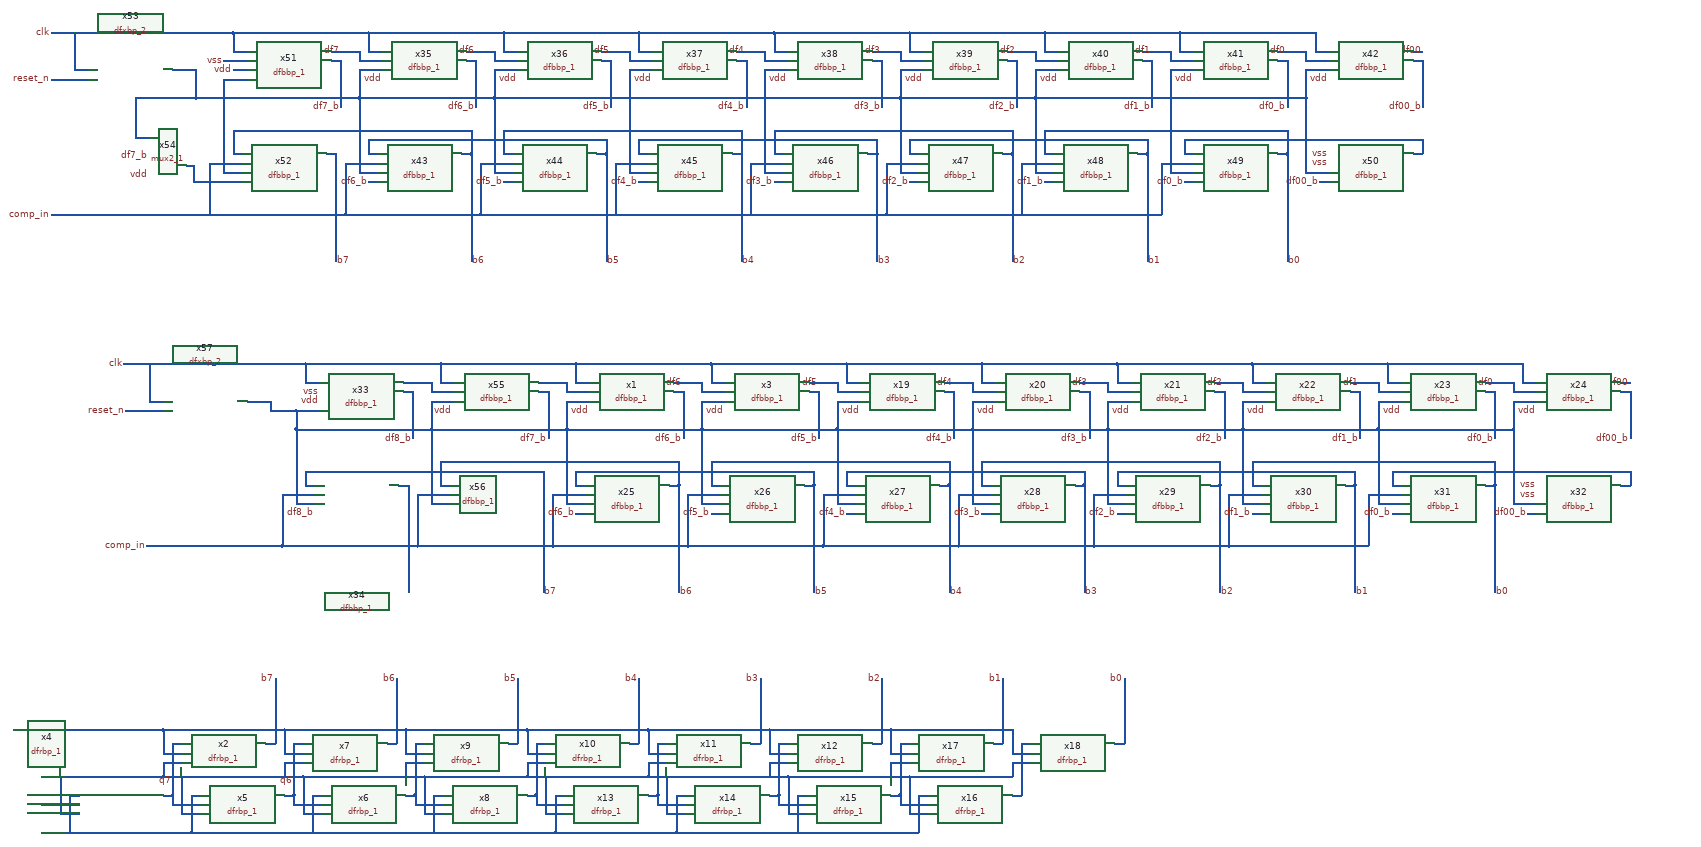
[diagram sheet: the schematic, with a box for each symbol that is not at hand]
v {xschem version=3.4.6RC file_version=1.2
}
G {}
K {}
V {}
S {}
E {}
N 440 -240 460 -240 {lab=q7}
N 420 -220 460 -220 {lab=#net1}
N 420 -270 420 -220 {lab=#net1}
N 160 -270 420 -270 {lab=#net1}
N 160 -110 240 -110 {lab=#net2}
N 220 -130 240 -130 {lab=#net3}
N 220 -130 220 -50 {lab=#net3}
N 160 -50 220 -50 {lab=#net3}
N 640 -240 660 -240 {lab=b7}
N 700 -240 720 -240 {lab=q6}
N 420 -200 460 -200 {lab=#net4}
N 420 -200 420 -170 {lab=#net4}
N 200 -90 240 -90 {lab=#net4}
N 200 -170 200 -90 {lab=#net4}
N 480 -130 500 -130 {lab=#net3}
N 480 -130 480 -50 {lab=#net3}
N 460 -90 500 -90 {lab=#net4}
N 460 -170 460 -90 {lab=#net4}
N 440 -110 500 -110 {lab=q7}
N 440 -130 440 -110 {lab=q7}
N 420 -130 440 -130 {lab=q7}
N 220 -50 480 -50 {lab=#net3}
N 440 -240 440 -130 {lab=q7}
N 680 -130 700 -130 {lab=q6}
N 700 -240 700 -130 {lab=q6}
N 680 -200 720 -200 {lab=#net4}
N 680 -200 680 -170 {lab=#net4}
N 420 -170 680 -170 {lab=#net4}
N 160 -170 420 -170 {lab=#net4}
N 680 -220 720 -220 {lab=#net1}
N 680 -270 680 -220 {lab=#net1}
N 420 -270 680 -270 {lab=#net1}
N 740 -130 760 -130 {lab=#net3}
N 740 -130 740 -50 {lab=#net3}
N 720 -90 760 -90 {lab=#net4}
N 720 -170 720 -90 {lab=#net4}
N 1000 -130 1020 -130 {lab=#net3}
N 1000 -130 1000 -50 {lab=#net3}
N 980 -90 1020 -90 {lab=#net4}
N 980 -170 980 -90 {lab=#net4}
N 960 -110 1020 -110 {lab=#net5}
N 960 -130 960 -110 {lab=#net5}
N 940 -130 960 -130 {lab=#net5}
N 740 -50 1000 -50 {lab=#net3}
N 960 -240 960 -130 {lab=#net5}
N 700 -110 760 -110 {lab=q6}
N 700 -130 700 -110 {lab=q6}
N 480 -50 740 -50 {lab=#net3}
N 680 -170 720 -170 {lab=#net4}
N 960 -240 980 -240 {lab=#net5}
N 720 -170 980 -170 {lab=#net4}
N 940 -220 980 -220 {lab=#net1}
N 940 -270 940 -220 {lab=#net1}
N 680 -270 940 -270 {lab=#net1}
N 940 -200 980 -200 {lab=#net4}
N 940 -200 940 -170 {lab=#net4}
N 1160 -240 1180 -240 {lab=b5}
N 1180 -380 1180 -240 {lab=b5}
N 900 -240 920 -240 {lab=b6}
N 920 -380 920 -240 {lab=b6}
N 660 -380 660 -240 {lab=b7}
N 1200 -130 1220 -130 {lab=#net6}
N 1220 -240 1220 -130 {lab=#net6}
N 1220 -240 1240 -240 {lab=#net6}
N 1200 -220 1240 -220 {lab=#net1}
N 1200 -270 1200 -220 {lab=#net1}
N 940 -270 1200 -270 {lab=#net1}
N 1200 -200 1240 -200 {lab=#net4}
N 1200 -200 1200 -170 {lab=#net4}
N 980 -170 1200 -170 {lab=#net4}
N 1420 -240 1440 -240 {lab=b4}
N 1440 -380 1440 -240 {lab=b4}
N 1480 -240 1500 -240 {lab=#net7}
N 1460 -220 1500 -220 {lab=#net1}
N 1460 -270 1460 -220 {lab=#net1}
N 1260 -130 1280 -130 {lab=#net3}
N 1260 -130 1260 -50 {lab=#net3}
N 1680 -240 1700 -240 {lab=b3}
N 1740 -240 1760 -240 {lab=#net8}
N 1460 -200 1500 -200 {lab=#net4}
N 1460 -200 1460 -170 {lab=#net4}
N 1520 -130 1540 -130 {lab=#net3}
N 1520 -130 1520 -50 {lab=#net3}
N 1500 -90 1540 -90 {lab=#net4}
N 1500 -170 1500 -90 {lab=#net4}
N 1480 -110 1540 -110 {lab=#net7}
N 1480 -130 1480 -110 {lab=#net7}
N 1460 -130 1480 -130 {lab=#net7}
N 1260 -50 1520 -50 {lab=#net3}
N 1480 -240 1480 -130 {lab=#net7}
N 1720 -130 1740 -130 {lab=#net8}
N 1740 -240 1740 -130 {lab=#net8}
N 1720 -200 1760 -200 {lab=#net4}
N 1720 -200 1720 -170 {lab=#net4}
N 1460 -170 1720 -170 {lab=#net4}
N 1720 -220 1760 -220 {lab=#net1}
N 1720 -270 1720 -220 {lab=#net1}
N 1460 -270 1720 -270 {lab=#net1}
N 1780 -130 1800 -130 {lab=#net3}
N 1780 -130 1780 -50 {lab=#net3}
N 1760 -90 1800 -90 {lab=#net4}
N 1760 -170 1760 -90 {lab=#net4}
N 2040 -130 2060 -130 {lab=#net3}
N 2040 -130 2040 -50 {lab=#net3}
N 2020 -90 2060 -90 {lab=#net4}
N 2020 -170 2020 -90 {lab=#net4}
N 2000 -110 2060 -110 {lab=#net9}
N 2000 -130 2000 -110 {lab=#net9}
N 1980 -130 2000 -130 {lab=#net9}
N 1780 -50 2040 -50 {lab=#net3}
N 2000 -240 2000 -130 {lab=#net9}
N 1740 -110 1800 -110 {lab=#net8}
N 1740 -130 1740 -110 {lab=#net8}
N 1520 -50 1780 -50 {lab=#net3}
N 1720 -170 1760 -170 {lab=#net4}
N 2000 -240 2020 -240 {lab=#net9}
N 1760 -170 2020 -170 {lab=#net4}
N 1980 -220 2020 -220 {lab=#net1}
N 1980 -270 1980 -220 {lab=#net1}
N 1720 -270 1980 -270 {lab=#net1}
N 1980 -200 2020 -200 {lab=#net4}
N 1980 -200 1980 -170 {lab=#net4}
N 2200 -240 2220 -240 {lab=b1}
N 2220 -380 2220 -240 {lab=b1}
N 1940 -240 1960 -240 {lab=b2}
N 1960 -380 1960 -240 {lab=b2}
N 1700 -380 1700 -240 {lab=b3}
N 2240 -130 2260 -130 {lab=#net10}
N 2260 -240 2260 -130 {lab=#net10}
N 2260 -240 2280 -240 {lab=#net10}
N 2240 -220 2280 -220 {lab=#net1}
N 2240 -270 2240 -220 {lab=#net1}
N 1980 -270 2240 -270 {lab=#net1}
N 2240 -200 2280 -200 {lab=#net4}
N 2240 -200 2240 -170 {lab=#net4}
N 2020 -170 2240 -170 {lab=#net4}
N 2460 -240 2480 -240 {lab=b0}
N 2480 -380 2480 -240 {lab=b0}
N 1200 -270 1460 -270 {lab=#net1}
N 1200 -170 1460 -170 {lab=#net4}
N 1000 -50 1260 -50 {lab=#net3}
N 1220 -130 1220 -110 {lab=#net6}
N 1220 -110 1280 -110 {lab=#net6}
N 1240 -90 1280 -90 {lab=#net4}
N 1240 -170 1240 -90 {lab=#net4}
N 100 -270 160 -270 {lab=#net1}
N 1305 -1015 1335 -1015 {lab=clk}
N 1285 -995 1335 -995 {lab=#net12}
N 2735 -975 2785 -975 {lab=#net13}
N 2735 -975 2735 -915 {lab=#net13}
N 2755 -1015 2785 -1015 {lab=clk}
N 2755 -1055 2755 -1015 {lab=clk}
N 2735 -995 2785 -995 {lab=df2}
N 2735 -1015 2735 -995 {lab=df2}
N 1515 -1015 1575 -1015 {lab=df6}
N 3025 -975 3075 -975 {lab=#net13}
N 3025 -975 3025 -915 {lab=#net13}
N 3045 -1015 3075 -1015 {lab=clk}
N 3045 -1055 3045 -1015 {lab=clk}
N 3025 -995 3075 -995 {lab=df1}
N 3025 -1015 3025 -995 {lab=df1}
N 2965 -1015 3025 -1015 {lab=df1}
N 3315 -975 3365 -975 {lab=#net13}
N 3315 -975 3315 -915 {lab=#net13}
N 3335 -1015 3365 -1015 {lab=clk}
N 3335 -1055 3335 -1015 {lab=clk}
N 3315 -995 3365 -995 {lab=df0}
N 3315 -1015 3315 -995 {lab=df0}
N 3255 -1015 3315 -1015 {lab=df0}
N 1305 -1055 1595 -1055 {lab=clk}
N 2755 -1055 3045 -1055 {lab=clk}
N 3045 -1055 3335 -1055 {lab=clk}
N 1285 -915 1575 -915 {lab=#net13}
N 2735 -915 3025 -915 {lab=#net13}
N 3025 -915 3315 -915 {lab=#net13}
N 1515 -995 1535 -995 {lab=df6_b}
N 1535 -995 1535 -895 {lab=df6_b}
N 2965 -995 2985 -995 {lab=df1_b}
N 2985 -995 2985 -895 {lab=df1_b}
N 3255 -995 3275 -995 {lab=df0_b}
N 3275 -995 3275 -895 {lab=df0_b}
N 3545 -995 3565 -995 {lab=df00_b}
N 3565 -995 3565 -895 {lab=df00_b}
N 3545 -1015 3565 -1015 {lab=df00}
N 1575 -975 1625 -975 {lab=#net13}
N 1575 -975 1575 -915 {lab=#net13}
N 1595 -1015 1625 -1015 {lab=clk}
N 1595 -1055 1595 -1015 {lab=clk}
N 1575 -995 1625 -995 {lab=df6}
N 1575 -1015 1575 -995 {lab=df6}
N 1805 -1015 1865 -1015 {lab=df5}
N 1595 -1055 1885 -1055 {lab=clk}
N 1575 -915 1865 -915 {lab=#net13}
N 1805 -995 1825 -995 {lab=df5_b}
N 1825 -995 1825 -895 {lab=df5_b}
N 1865 -975 1915 -975 {lab=#net13}
N 1865 -975 1865 -915 {lab=#net13}
N 1885 -1015 1915 -1015 {lab=clk}
N 1885 -1055 1885 -1015 {lab=clk}
N 1865 -995 1915 -995 {lab=df5}
N 1865 -1015 1865 -995 {lab=df5}
N 2095 -1015 2155 -1015 {lab=df4}
N 1885 -1055 2175 -1055 {lab=clk}
N 1865 -915 2155 -915 {lab=#net13}
N 2095 -995 2115 -995 {lab=df4_b}
N 2115 -995 2115 -895 {lab=df4_b}
N 2155 -975 2205 -975 {lab=#net13}
N 2155 -975 2155 -915 {lab=#net13}
N 2175 -1015 2205 -1015 {lab=clk}
N 2175 -1055 2175 -1015 {lab=clk}
N 2155 -995 2205 -995 {lab=df4}
N 2155 -1015 2155 -995 {lab=df4}
N 2385 -1015 2445 -1015 {lab=df3}
N 2175 -1055 2465 -1055 {lab=clk}
N 2155 -915 2445 -915 {lab=#net13}
N 2385 -995 2405 -995 {lab=df3_b}
N 2405 -995 2405 -895 {lab=df3_b}
N 2445 -975 2495 -975 {lab=#net13}
N 2445 -975 2445 -915 {lab=#net13}
N 2465 -1015 2495 -1015 {lab=clk}
N 2465 -1055 2465 -1015 {lab=clk}
N 2445 -995 2495 -995 {lab=df3}
N 2445 -1015 2445 -995 {lab=df3}
N 2675 -1015 2735 -1015 {lab=df2}
N 2465 -1055 2755 -1055 {lab=clk}
N 2445 -915 2735 -915 {lab=#net13}
N 2675 -995 2695 -995 {lab=df2_b}
N 2695 -995 2695 -895 {lab=df2_b}
N 3345 -735 3365 -735 {lab=df00_b}
N 3545 -795 3565 -795 {lab=#net14}
N 3565 -825 3565 -795 {lab=#net14}
N 3055 -795 3075 -795 {lab=#net14}
N 3055 -825 3055 -795 {lab=#net14}
N 3055 -735 3075 -735 {lab=df0_b}
N 3255 -795 3275 -795 {lab=b0}
N 3275 -845 3275 -795 {lab=b0}
N 2755 -845 2755 -795 {lab=b0}
N 2755 -795 2775 -795 {lab=b0}
N 2755 -845 3275 -845 {lab=b0}
N 2955 -795 2975 -795 {lab=b1}
N 2975 -825 2975 -795 {lab=b1}
N 2465 -795 2485 -795 {lab=b1}
N 2465 -825 2465 -795 {lab=b1}
N 2465 -825 2975 -825 {lab=b1}
N 2665 -795 2685 -795 {lab=b2}
N 2685 -845 2685 -795 {lab=b2}
N 2175 -795 2195 -795 {lab=b2}
N 2175 -845 2175 -795 {lab=b2}
N 2175 -845 2685 -845 {lab=b2}
N 2175 -735 2195 -735 {lab=df3_b}
N 2465 -735 2485 -735 {lab=df2_b}
N 2755 -735 2775 -735 {lab=df1_b}
N 2125 -775 2125 -665 {lab=#net15}
N 2415 -775 2415 -665 {lab=#net15}
N 2375 -795 2395 -795 {lab=b3}
N 2705 -775 2705 -665 {lab=#net15}
N 1885 -795 1905 -795 {lab=b3}
N 1885 -825 1885 -795 {lab=b3}
N 1885 -825 2395 -825 {lab=b3}
N 2085 -795 2105 -795 {lab=b4}
N 2105 -845 2105 -795 {lab=b4}
N 1595 -795 1615 -795 {lab=b4}
N 1595 -845 1595 -795 {lab=b4}
N 1595 -845 2105 -845 {lab=b4}
N 1595 -735 1615 -735 {lab=df5_b}
N 1885 -735 1905 -735 {lab=df4_b}
N 1835 -775 1835 -665 {lab=#net15}
N 1795 -795 1815 -795 {lab=b5}
N 2395 -825 2395 -795 {lab=b3}
N 1545 -775 1545 -665 {lab=#net15}
N 725 -795 745 -795 {lab=b7}
N 1505 -795 1525 -795 {lab=b6}
N 1525 -845 1525 -795 {lab=b6}
N 1815 -825 1815 -795 {lab=b5}
N 1545 -775 1615 -775 {lab=#net15}
N 1525 -795 1525 -565 {lab=b6}
N 1815 -795 1815 -565 {lab=b5}
N 1835 -775 1905 -775 {lab=#net15}
N 2125 -775 2195 -775 {lab=#net15}
N 2105 -795 2105 -565 {lab=b4}
N 2415 -775 2485 -775 {lab=#net15}
N 2395 -795 2395 -565 {lab=b3}
N 2685 -795 2685 -565 {lab=b2}
N 2705 -775 2775 -775 {lab=#net15}
N 2975 -795 2975 -565 {lab=b1}
N 3005 -775 3075 -775 {lab=#net15}
N 3275 -795 3275 -565 {lab=b0}
N 3055 -825 3565 -825 {lab=#net14}
N 1225 -995 1245 -995 {lab=df7_b}
N 1245 -995 1245 -895 {lab=df7_b}
N 1305 -825 1305 -795 {lab=b5}
N 1305 -795 1325 -795 {lab=b5}
N 925 -795 945 -795 {lab=#net16}
N 1545 -665 1835 -665 {lab=#net15}
N 1835 -665 2125 -665 {lab=#net15}
N 2125 -665 2415 -665 {lab=#net15}
N 2415 -665 2705 -665 {lab=#net15}
N 2705 -665 3005 -665 {lab=#net15}
N 3005 -775 3005 -665 {lab=#net15}
N 1305 -1055 1305 -1015 {lab=clk}
N 945 -795 945 -565 {lab=#net16}
N 1255 -665 1545 -665 {lab=#net15}
N 1305 -825 1815 -825 {lab=b5}
N 1015 -845 1525 -845 {lab=b6}
N 1305 -735 1325 -735 {lab=df6_b}
N 1285 -755 1325 -755 {lab=#net13}
N 1575 -915 1575 -755 {lab=#net13}
N 1575 -755 1615 -755 {lab=#net13}
N 1865 -915 1865 -755 {lab=#net13}
N 1865 -755 1905 -755 {lab=#net13}
N 2155 -915 2155 -755 {lab=#net13}
N 2155 -755 2195 -755 {lab=#net13}
N 2445 -915 2445 -755 {lab=#net13}
N 2445 -755 2485 -755 {lab=#net13}
N 2735 -915 2735 -755 {lab=#net13}
N 2735 -755 2775 -755 {lab=#net13}
N 3025 -915 3025 -755 {lab=#net13}
N 3025 -755 3075 -755 {lab=#net13}
N 3315 -915 3315 -755 {lab=#net13}
N 3315 -755 3365 -755 {lab=#net13}
N 280 -1765 570 -1765 {lab=clk}
N 840 -1685 890 -1685 {lab=#net17}
N 860 -1725 890 -1725 {lab=clk}
N 570 -1765 570 -1725 {lab=clk}
N 840 -1705 890 -1705 {lab=df7}
N 2290 -1685 2340 -1685 {lab=#net17}
N 2290 -1685 2290 -1625 {lab=#net17}
N 2310 -1725 2340 -1725 {lab=clk}
N 2310 -1765 2310 -1725 {lab=clk}
N 2290 -1705 2340 -1705 {lab=df2}
N 2290 -1725 2290 -1705 {lab=df2}
N 1070 -1725 1130 -1725 {lab=df6}
N 2580 -1685 2630 -1685 {lab=#net17}
N 2580 -1685 2580 -1625 {lab=#net17}
N 2600 -1725 2630 -1725 {lab=clk}
N 2600 -1765 2600 -1725 {lab=clk}
N 2580 -1705 2630 -1705 {lab=df1}
N 2580 -1725 2580 -1705 {lab=df1}
N 2520 -1725 2580 -1725 {lab=df1}
N 2870 -1685 2920 -1685 {lab=#net17}
N 2870 -1685 2870 -1625 {lab=#net17}
N 2890 -1725 2920 -1725 {lab=clk}
N 2890 -1765 2890 -1725 {lab=clk}
N 2870 -1705 2920 -1705 {lab=df0}
N 2870 -1725 2870 -1705 {lab=df0}
N 2810 -1725 2870 -1725 {lab=df0}
N 860 -1765 1150 -1765 {lab=clk}
N 2310 -1765 2600 -1765 {lab=clk}
N 2600 -1765 2890 -1765 {lab=clk}
N 840 -1625 1130 -1625 {lab=#net17}
N 2290 -1625 2580 -1625 {lab=#net17}
N 2580 -1625 2870 -1625 {lab=#net17}
N 1070 -1705 1090 -1705 {lab=df6_b}
N 1090 -1705 1090 -1605 {lab=df6_b}
N 2520 -1705 2540 -1705 {lab=df1_b}
N 2540 -1705 2540 -1605 {lab=df1_b}
N 2810 -1705 2830 -1705 {lab=df0_b}
N 2830 -1705 2830 -1605 {lab=df0_b}
N 3100 -1705 3120 -1705 {lab=df00_b}
N 3120 -1705 3120 -1605 {lab=df00_b}
N 3100 -1725 3120 -1725 {lab=df00}
N 1130 -1685 1180 -1685 {lab=#net17}
N 1130 -1685 1130 -1625 {lab=#net17}
N 1150 -1725 1180 -1725 {lab=clk}
N 1150 -1765 1150 -1725 {lab=clk}
N 1130 -1705 1180 -1705 {lab=df6}
N 1130 -1725 1130 -1705 {lab=df6}
N 1360 -1725 1420 -1725 {lab=df5}
N 1150 -1765 1440 -1765 {lab=clk}
N 1130 -1625 1420 -1625 {lab=#net17}
N 1360 -1705 1380 -1705 {lab=df5_b}
N 1380 -1705 1380 -1605 {lab=df5_b}
N 1420 -1685 1470 -1685 {lab=#net17}
N 1420 -1685 1420 -1625 {lab=#net17}
N 1440 -1725 1470 -1725 {lab=clk}
N 1440 -1765 1440 -1725 {lab=clk}
N 1420 -1705 1470 -1705 {lab=df5}
N 1420 -1725 1420 -1705 {lab=df5}
N 1650 -1725 1710 -1725 {lab=df4}
N 1440 -1765 1730 -1765 {lab=clk}
N 1420 -1625 1710 -1625 {lab=#net17}
N 1650 -1705 1670 -1705 {lab=df4_b}
N 1670 -1705 1670 -1605 {lab=df4_b}
N 1710 -1685 1760 -1685 {lab=#net17}
N 1710 -1685 1710 -1625 {lab=#net17}
N 1730 -1725 1760 -1725 {lab=clk}
N 1730 -1765 1730 -1725 {lab=clk}
N 1710 -1705 1760 -1705 {lab=df4}
N 1710 -1725 1710 -1705 {lab=df4}
N 1940 -1725 2000 -1725 {lab=df3}
N 1730 -1765 2020 -1765 {lab=clk}
N 1710 -1625 2000 -1625 {lab=#net17}
N 1940 -1705 1960 -1705 {lab=df3_b}
N 1960 -1705 1960 -1605 {lab=df3_b}
N 2000 -1685 2050 -1685 {lab=#net17}
N 2000 -1685 2000 -1625 {lab=#net17}
N 2020 -1725 2050 -1725 {lab=clk}
N 2020 -1765 2020 -1725 {lab=clk}
N 2000 -1705 2050 -1705 {lab=df3}
N 2000 -1725 2000 -1705 {lab=df3}
N 2230 -1725 2290 -1725 {lab=df2}
N 2020 -1765 2310 -1765 {lab=clk}
N 2000 -1625 2290 -1625 {lab=#net17}
N 2230 -1705 2250 -1705 {lab=df2_b}
N 2250 -1705 2250 -1605 {lab=df2_b}
N 2900 -1445 2920 -1445 {lab=df00_b}
N 3100 -1505 3120 -1505 {lab=#net18}
N 3120 -1535 3120 -1505 {lab=#net18}
N 2610 -1505 2630 -1505 {lab=#net18}
N 2610 -1535 2610 -1505 {lab=#net18}
N 2610 -1445 2630 -1445 {lab=df0_b}
N 2810 -1505 2830 -1505 {lab=b0}
N 2830 -1555 2830 -1505 {lab=b0}
N 2310 -1555 2310 -1505 {lab=b0}
N 2310 -1505 2330 -1505 {lab=b0}
N 2310 -1555 2830 -1555 {lab=b0}
N 2510 -1505 2530 -1505 {lab=b1}
N 2530 -1535 2530 -1505 {lab=b1}
N 2020 -1505 2040 -1505 {lab=b1}
N 2020 -1535 2020 -1505 {lab=b1}
N 2020 -1535 2530 -1535 {lab=b1}
N 2220 -1505 2240 -1505 {lab=b2}
N 2240 -1555 2240 -1505 {lab=b2}
N 1730 -1505 1750 -1505 {lab=b2}
N 1730 -1555 1730 -1505 {lab=b2}
N 1730 -1555 2240 -1555 {lab=b2}
N 1730 -1445 1750 -1445 {lab=df3_b}
N 2020 -1445 2040 -1445 {lab=df2_b}
N 2310 -1445 2330 -1445 {lab=df1_b}
N 1680 -1485 1680 -1375 {lab=comp_in}
N 1970 -1485 1970 -1375 {lab=comp_in}
N 1930 -1505 1950 -1505 {lab=b3}
N 2260 -1485 2260 -1375 {lab=comp_in}
N 1440 -1505 1460 -1505 {lab=b3}
N 1440 -1535 1440 -1505 {lab=b3}
N 1440 -1535 1950 -1535 {lab=b3}
N 1640 -1505 1660 -1505 {lab=b4}
N 1660 -1555 1660 -1505 {lab=b4}
N 1150 -1505 1170 -1505 {lab=b4}
N 1150 -1555 1150 -1505 {lab=b4}
N 1150 -1555 1660 -1555 {lab=b4}
N 1150 -1445 1170 -1445 {lab=df5_b}
N 1440 -1445 1460 -1445 {lab=df4_b}
N 1390 -1485 1390 -1375 {lab=comp_in}
N 1350 -1505 1370 -1505 {lab=b5}
N 1950 -1535 1950 -1505 {lab=b3}
N 1100 -1485 1100 -1375 {lab=comp_in}
N 570 -1505 590 -1505 {lab=b6}
N 1060 -1505 1080 -1505 {lab=b6}
N 1080 -1555 1080 -1505 {lab=b6}
N 570 -1445 590 -1445 {lab=#net19}
N 1370 -1535 1370 -1505 {lab=b5}
N 520 -1485 520 -1375 {lab=comp_in}
N 520 -1485 590 -1485 {lab=comp_in}
N 1100 -1485 1170 -1485 {lab=comp_in}
N 1080 -1505 1080 -1275 {lab=b6}
N 1370 -1505 1370 -1275 {lab=b5}
N 1390 -1485 1460 -1485 {lab=comp_in}
N 1680 -1485 1750 -1485 {lab=comp_in}
N 1660 -1505 1660 -1275 {lab=b4}
N 1970 -1485 2040 -1485 {lab=comp_in}
N 1950 -1505 1950 -1275 {lab=b3}
N 2240 -1505 2240 -1275 {lab=b2}
N 2260 -1485 2330 -1485 {lab=comp_in}
N 2530 -1505 2530 -1275 {lab=b1}
N 2560 -1485 2630 -1485 {lab=comp_in}
N 2830 -1505 2830 -1275 {lab=b0}
N 2610 -1535 3120 -1535 {lab=#net18}
N 570 -1725 600 -1725 {lab=clk}
N 550 -1705 600 -1705 {lab=vss}
N 780 -1725 840 -1725 {lab=df7}
N 550 -1625 840 -1625 {lab=#net17}
N 780 -1705 800 -1705 {lab=df7_b}
N 800 -1705 800 -1605 {lab=df7_b}
N 840 -1685 840 -1625 {lab=#net17}
N 840 -1725 840 -1705 {lab=df7}
N 810 -1485 880 -1485 {lab=comp_in}
N 860 -1535 860 -1505 {lab=b5}
N 860 -1505 880 -1505 {lab=b5}
N 770 -1505 790 -1505 {lab=b7}
N 570 -1555 570 -1505 {lab=b6}
N 180 -1375 230 -1375 {lab=comp_in}
N 230 -1375 520 -1375 {lab=comp_in}
N 1100 -1375 1390 -1375 {lab=comp_in}
N 1390 -1375 1680 -1375 {lab=comp_in}
N 1680 -1375 1970 -1375 {lab=comp_in}
N 1970 -1375 2260 -1375 {lab=comp_in}
N 2260 -1375 2560 -1375 {lab=comp_in}
N 2560 -1485 2560 -1375 {lab=comp_in}
N 570 -1765 860 -1765 {lab=clk}
N 860 -1765 860 -1725 {lab=clk}
N 790 -1505 790 -1275 {lab=b7}
N 810 -1485 810 -1375 {lab=comp_in}
N 520 -1375 810 -1375 {lab=comp_in}
N 810 -1375 1100 -1375 {lab=comp_in}
N 860 -1535 1370 -1535 {lab=b5}
N 570 -1555 1080 -1555 {lab=b6}
N 860 -1445 880 -1445 {lab=df6_b}
N 550 -1625 550 -1465 {lab=#net17}
N 550 -1465 590 -1465 {lab=#net17}
N 840 -1625 840 -1465 {lab=#net17}
N 840 -1465 880 -1465 {lab=#net17}
N 1130 -1625 1130 -1465 {lab=#net17}
N 1130 -1465 1170 -1465 {lab=#net17}
N 1420 -1625 1420 -1465 {lab=#net17}
N 1420 -1465 1460 -1465 {lab=#net17}
N 1710 -1625 1710 -1465 {lab=#net17}
N 1710 -1465 1750 -1465 {lab=#net17}
N 2000 -1625 2000 -1465 {lab=#net17}
N 2000 -1465 2040 -1465 {lab=#net17}
N 2290 -1625 2290 -1465 {lab=#net17}
N 2290 -1465 2330 -1465 {lab=#net17}
N 2580 -1625 2580 -1465 {lab=#net17}
N 2580 -1465 2630 -1465 {lab=#net17}
N 2870 -1625 2870 -1465 {lab=#net17}
N 2870 -1465 2920 -1465 {lab=#net17}
N 180 -1665 260 -1665 {lab=reset_n}
N 180 -1765 280 -1765 {lab=clk}
N 230 -1685 260 -1685 {lab=clk}
N 230 -1765 230 -1685 {lab=clk}
N 570 -1685 600 -1685 {lab=vdd}
N 490 -1685 490 -1625 {lab=#net17}
N 550 -1665 550 -1625 {lab=#net17}
N 550 -1665 600 -1665 {lab=#net17}
N 490 -1625 550 -1625 {lab=#net17}
N 440 -1685 490 -1685 {lab=#net17}
N 470 -1480 485 -1480 {lab=#net19}
N 485 -1480 485 -1445 {lab=#net19}
N 485 -1445 570 -1445 {lab=#net19}
N 360 -1625 490 -1625 {lab=#net17}
N 360 -1625 360 -1540 {lab=#net17}
N 360 -1540 390 -1540 {lab=#net17}
N 1225 -1015 1285 -1015 {lab=#net12}
N 1285 -1015 1285 -995 {lab=#net12}
N 1015 -795 1035 -795 {lab=b6}
N 1235 -795 1235 -565 {lab=b7}
N 1285 -915 1285 -755 {lab=#net13}
N 1015 -845 1015 -795 {lab=b6}
N 1235 -825 1235 -795 {lab=b7}
N 725 -825 725 -795 {lab=b7}
N 725 -825 1235 -825 {lab=b7}
N 995 -755 1035 -755 {lab=#net13}
N 995 -915 995 -755 {lab=#net13}
N 995 -915 1285 -915 {lab=#net13}
N 705 -755 745 -755 {lab=#net20}
N 705 -915 705 -755 {lab=#net20}
N 995 -995 1045 -995 {lab=#net21}
N 935 -1015 995 -1015 {lab=#net21}
N 995 -1015 995 -995 {lab=#net21}
N 725 -1015 755 -1015 {lab=clk}
N 725 -1055 725 -1015 {lab=clk}
N 1015 -1055 1305 -1055 {lab=clk}
N 725 -1055 1015 -1055 {lab=clk}
N 1015 -1015 1045 -1015 {lab=clk}
N 1015 -1055 1015 -1015 {lab=clk}
N 705 -955 705 -915 {lab=#net20}
N 705 -955 755 -955 {lab=#net20}
N 935 -995 955 -995 {lab=df8_b}
N 955 -995 955 -895 {lab=df8_b}
N 385 -665 675 -665 {lab=#net15}
N 675 -665 965 -665 {lab=#net15}
N 965 -665 1255 -665 {lab=#net15}
N 435 -1055 725 -1055 {lab=clk}
N 335 -1055 435 -1055 {lab=clk}
N 340 -955 420 -955 {lab=reset_n}
N 390 -975 420 -975 {lab=clk}
N 390 -1055 390 -975 {lab=clk}
N 600 -975 650 -975 {lab=#net20}
N 650 -955 705 -955 {lab=#net20}
N 650 -975 650 -955 {lab=#net20}
N 1255 -775 1255 -665 {lab=#net15}
N 1255 -775 1325 -775 {lab=#net15}
N 965 -775 965 -665 {lab=#net15}
N 965 -775 1035 -775 {lab=#net15}
N 675 -775 675 -665 {lab=#net15}
N 675 -775 745 -775 {lab=#net15}
N 705 -915 995 -915 {lab=#net13}
N 1285 -975 1335 -975 {lab=#net13}
N 1285 -975 1285 -915 {lab=#net13}
N 995 -975 1045 -975 {lab=#net13}
N 995 -975 995 -915 {lab=#net13}
C {sky130_stdcells/dfrbp_1.sym} 550 -220 0 0 {name=x2 VGND=vss VNB=vss VPB=vdd VPWR=vdd prefix=sky130_fd_sc_hd__ }
C {sky130_stdcells/dfrbp_1.sym} 810 -220 0 0 {name=x7 VGND=vss VNB=vss VPB=vdd VPWR=vdd prefix=sky130_fd_sc_hd__ }
C {sky130_stdcells/dfrbp_1.sym} 330 -110 0 0 {name=x4 VGND=vss VNB=vss VPB=vdd VPWR=vdd prefix=sky130_fd_sc_hd__ }
C {sky130_stdcells/dfrbp_1.sym} 590 -110 0 0 {name=x5 VGND=vss VNB=vss VPB=vdd VPWR=vdd prefix=sky130_fd_sc_hd__ }
C {sky130_stdcells/dfrbp_1.sym} 850 -110 0 0 {name=x6 VGND=vss VNB=vss VPB=vdd VPWR=vdd prefix=sky130_fd_sc_hd__ }
C {sky130_stdcells/dfrbp_1.sym} 1110 -110 0 0 {name=x8 VGND=vss VNB=vss VPB=vdd VPWR=vdd prefix=sky130_fd_sc_hd__ }
C {sky130_stdcells/dfrbp_1.sym} 1070 -220 0 0 {name=x9 VGND=vss VNB=vss VPB=vdd VPWR=vdd prefix=sky130_fd_sc_hd__ }
C {sky130_stdcells/dfrbp_1.sym} 1330 -220 0 0 {name=x10 VGND=vss VNB=vss VPB=vdd VPWR=vdd prefix=sky130_fd_sc_hd__ }
C {sky130_stdcells/dfrbp_1.sym} 1590 -220 0 0 {name=x11 VGND=vss VNB=vss VPB=vdd VPWR=vdd prefix=sky130_fd_sc_hd__ }
C {sky130_stdcells/dfrbp_1.sym} 1850 -220 0 0 {name=x12 VGND=vss VNB=vss VPB=vdd VPWR=vdd prefix=sky130_fd_sc_hd__ }
C {sky130_stdcells/dfrbp_1.sym} 1370 -110 0 0 {name=x13 VGND=vss VNB=vss VPB=vdd VPWR=vdd prefix=sky130_fd_sc_hd__ }
C {sky130_stdcells/dfrbp_1.sym} 1630 -110 0 0 {name=x14 VGND=vss VNB=vss VPB=vdd VPWR=vdd prefix=sky130_fd_sc_hd__ }
C {sky130_stdcells/dfrbp_1.sym} 1890 -110 0 0 {name=x15 VGND=vss VNB=vss VPB=vdd VPWR=vdd prefix=sky130_fd_sc_hd__ }
C {sky130_stdcells/dfrbp_1.sym} 2150 -110 0 0 {name=x16 VGND=vss VNB=vss VPB=vdd VPWR=vdd prefix=sky130_fd_sc_hd__ }
C {sky130_stdcells/dfrbp_1.sym} 2110 -220 0 0 {name=x17 VGND=vss VNB=vss VPB=vdd VPWR=vdd prefix=sky130_fd_sc_hd__ }
C {sky130_stdcells/dfrbp_1.sym} 2370 -220 0 0 {name=x18 VGND=vss VNB=vss VPB=vdd VPWR=vdd prefix=sky130_fd_sc_hd__ }
C {lab_pin.sym} 2480 -380 0 0 {name=p10 sig_type=std_logic lab=b0
}
C {lab_pin.sym} 2220 -380 0 0 {name=p11 sig_type=std_logic lab=b1
}
C {lab_pin.sym} 1960 -380 0 0 {name=p14 sig_type=std_logic lab=b2
}
C {lab_pin.sym} 1700 -380 0 0 {name=p16 sig_type=std_logic lab=b3
}
C {lab_pin.sym} 1440 -380 0 0 {name=p17 sig_type=std_logic lab=b4
}
C {lab_pin.sym} 1180 -380 0 0 {name=p18 sig_type=std_logic lab=b5
}
C {lab_pin.sym} 920 -380 0 0 {name=p20 sig_type=std_logic lab=b6
}
C {lab_pin.sym} 660 -380 0 0 {name=p21 sig_type=std_logic lab=b7
}
C {lab_pin.sym} 440 -160 0 0 {name=p54 sig_type=std_logic lab=q7
}
C {lab_pin.sym} 700 -160 0 0 {name=p53 sig_type=std_logic lab=q6
}
C {lab_pin.sym} 1335 -955 0 0 {name=p24 sig_type=std_logic lab=vdd
}
C {lab_pin.sym} 2785 -955 0 0 {name=p26 sig_type=std_logic lab=vdd
}
C {lab_pin.sym} 3075 -955 0 0 {name=p1 sig_type=std_logic lab=vdd
}
C {lab_pin.sym} 3365 -955 0 0 {name=p55 sig_type=std_logic lab=vdd
}
C {lab_pin.sym} 1535 -895 0 0 {name=p56 sig_type=std_logic lab=df6_b}
C {lab_pin.sym} 2985 -895 0 0 {name=p57 sig_type=std_logic lab=df1_b}
C {lab_pin.sym} 3275 -895 0 0 {name=p58 sig_type=std_logic lab=df0_b}
C {lab_pin.sym} 3565 -895 0 0 {name=p59 sig_type=std_logic lab=df00_b}
C {lab_pin.sym} 1535 -1015 1 0 {name=p62 sig_type=std_logic lab=df6}
C {lab_pin.sym} 2985 -1015 1 0 {name=p64 sig_type=std_logic lab=df1}
C {lab_pin.sym} 3275 -1015 1 0 {name=p65 sig_type=std_logic lab=df0}
C {lab_pin.sym} 3565 -1015 1 0 {name=p66 sig_type=std_logic lab=df00}
C {lab_pin.sym} 1625 -955 0 0 {name=p67 sig_type=std_logic lab=vdd
}
C {lab_pin.sym} 1825 -895 0 0 {name=p68 sig_type=std_logic lab=df5_b}
C {lab_pin.sym} 1825 -1015 1 0 {name=p69 sig_type=std_logic lab=df5}
C {lab_pin.sym} 1915 -955 0 0 {name=p70 sig_type=std_logic lab=vdd
}
C {lab_pin.sym} 2115 -895 0 0 {name=p71 sig_type=std_logic lab=df4_b}
C {lab_pin.sym} 2115 -1015 1 0 {name=p72 sig_type=std_logic lab=df4}
C {lab_pin.sym} 2205 -955 0 0 {name=p73 sig_type=std_logic lab=vdd
}
C {lab_pin.sym} 2405 -895 0 0 {name=p74 sig_type=std_logic lab=df3_b}
C {lab_pin.sym} 2405 -1015 1 0 {name=p75 sig_type=std_logic lab=df3}
C {lab_pin.sym} 2495 -955 0 0 {name=p76 sig_type=std_logic lab=vdd
}
C {lab_pin.sym} 2695 -895 0 0 {name=p77 sig_type=std_logic lab=df2_b}
C {lab_pin.sym} 2695 -1015 1 0 {name=p78 sig_type=std_logic lab=df2}
C {lab_pin.sym} 3345 -735 3 0 {name=p79 sig_type=std_logic lab=df00_b}
C {lab_pin.sym} 3055 -735 3 0 {name=p80 sig_type=std_logic lab=df0_b}
C {lab_pin.sym} 2175 -735 3 0 {name=p84 sig_type=std_logic lab=df3_b}
C {lab_pin.sym} 2465 -735 3 0 {name=p85 sig_type=std_logic lab=df2_b}
C {lab_pin.sym} 2755 -735 3 0 {name=p86 sig_type=std_logic lab=df1_b}
C {lab_pin.sym} 2685 -565 2 0 {name=p90 sig_type=std_logic lab=b2}
C {lab_pin.sym} 2395 -565 2 0 {name=p91 sig_type=std_logic lab=b3}
C {lab_pin.sym} 2975 -565 2 0 {name=p92 sig_type=std_logic lab=b1}
C {lab_pin.sym} 3275 -565 2 0 {name=p93 sig_type=std_logic lab=b0}
C {lab_pin.sym} 1595 -735 3 0 {name=p96 sig_type=std_logic lab=df5_b}
C {lab_pin.sym} 1885 -735 3 0 {name=p97 sig_type=std_logic lab=df4_b}
C {lab_pin.sym} 2105 -565 2 0 {name=p100 sig_type=std_logic lab=b4}
C {lab_pin.sym} 1815 -565 2 0 {name=p101 sig_type=std_logic lab=b5}
C {lab_pin.sym} 1525 -565 2 0 {name=p105 sig_type=std_logic lab=b6}
C {lab_pin.sym} 1235 -565 2 0 {name=p106 sig_type=std_logic lab=b7}
C {sky130_stdcells/dfbbp_1.sym} 1425 -985 0 0 {name=x1 VGND=vss VNB=vss VPB=vdd VPWR=vdd prefix=sky130_fd_sc_hd__ }
C {sky130_stdcells/dfbbp_1.sym} 1715 -985 0 0 {name=x3 VGND=vss VNB=vss VPB=vdd VPWR=vdd prefix=sky130_fd_sc_hd__ }
C {sky130_stdcells/dfbbp_1.sym} 2005 -985 0 0 {name=x19 VGND=vss VNB=vss VPB=vdd VPWR=vdd prefix=sky130_fd_sc_hd__ }
C {sky130_stdcells/dfbbp_1.sym} 2295 -985 0 0 {name=x20 VGND=vss VNB=vss VPB=vdd VPWR=vdd prefix=sky130_fd_sc_hd__ }
C {sky130_stdcells/dfbbp_1.sym} 2585 -985 0 0 {name=x21 VGND=vss VNB=vss VPB=vdd VPWR=vdd prefix=sky130_fd_sc_hd__ }
C {sky130_stdcells/dfbbp_1.sym} 2875 -985 0 0 {name=x22 VGND=vss VNB=vss VPB=vdd VPWR=vdd prefix=sky130_fd_sc_hd__ }
C {sky130_stdcells/dfbbp_1.sym} 3165 -985 0 0 {name=x23 VGND=vss VNB=vss VPB=vdd VPWR=vdd prefix=sky130_fd_sc_hd__ }
C {sky130_stdcells/dfbbp_1.sym} 3455 -985 0 0 {name=x24 VGND=vss VNB=vss VPB=vdd VPWR=vdd prefix=sky130_fd_sc_hd__ }
C {sky130_stdcells/dfbbp_1.sym} 1415 -765 0 0 {name=x25 VGND=vss VNB=vss VPB=vdd VPWR=vdd prefix=sky130_fd_sc_hd__ }
C {sky130_stdcells/dfbbp_1.sym} 1705 -765 0 0 {name=x26 VGND=vss VNB=vss VPB=vdd VPWR=vdd prefix=sky130_fd_sc_hd__ }
C {sky130_stdcells/dfbbp_1.sym} 1995 -765 0 0 {name=x27 VGND=vss VNB=vss VPB=vdd VPWR=vdd prefix=sky130_fd_sc_hd__ }
C {sky130_stdcells/dfbbp_1.sym} 2285 -765 0 0 {name=x28 VGND=vss VNB=vss VPB=vdd VPWR=vdd prefix=sky130_fd_sc_hd__ }
C {sky130_stdcells/dfbbp_1.sym} 2575 -765 0 0 {name=x29 VGND=vss VNB=vss VPB=vdd VPWR=vdd prefix=sky130_fd_sc_hd__ }
C {sky130_stdcells/dfbbp_1.sym} 2865 -765 0 0 {name=x30 VGND=vss VNB=vss VPB=vdd VPWR=vdd prefix=sky130_fd_sc_hd__ }
C {sky130_stdcells/dfbbp_1.sym} 3165 -765 0 0 {name=x31 VGND=vss VNB=vss VPB=vdd VPWR=vdd prefix=sky130_fd_sc_hd__ }
C {sky130_stdcells/dfbbp_1.sym} 3455 -765 0 0 {name=x32 VGND=vss VNB=vss VPB=vdd VPWR=vdd prefix=sky130_fd_sc_hd__ }
C {lab_pin.sym} 3365 -795 0 0 {name=p35 sig_type=std_logic lab=vss
}
C {lab_pin.sym} 3365 -775 0 0 {name=p36 sig_type=std_logic lab=vss
}
C {lab_pin.sym} 1245 -895 0 0 {name=p39 sig_type=std_logic lab=df7_b}
C {sky130_stdcells/dfbbp_1.sym} 845 -985 0 0 {name=x33 VGND=vss VNB=vss VPB=vdd VPWR=vdd prefix=sky130_fd_sc_hd__ }
C {sky130_stdcells/dfbbp_1.sym} 835 -765 0 0 {name=x34 VGND=vss VNB=vss VPB=vdd VPWR=vdd prefix=sky130_fd_sc_hd__ }
C {lab_pin.sym} 1305 -735 3 0 {name=p41 sig_type=std_logic lab=df6_b}
C {lab_pin.sym} 180 -1765 0 0 {name=p22 sig_type=std_logic lab=clk}
C {devices/lab_pin.sym} 550 -1705 0 0 {name=p2 lab=vss}
C {lab_pin.sym} 890 -1665 0 0 {name=p3 sig_type=std_logic lab=vdd
}
C {lab_pin.sym} 2340 -1665 0 0 {name=p4 sig_type=std_logic lab=vdd
}
C {lab_pin.sym} 2630 -1665 0 0 {name=p5 sig_type=std_logic lab=vdd
}
C {lab_pin.sym} 2920 -1665 0 0 {name=p6 sig_type=std_logic lab=vdd
}
C {lab_pin.sym} 1090 -1605 0 0 {name=p7 sig_type=std_logic lab=df6_b}
C {lab_pin.sym} 2540 -1605 0 0 {name=p8 sig_type=std_logic lab=df1_b}
C {lab_pin.sym} 2830 -1605 0 0 {name=p9 sig_type=std_logic lab=df0_b}
C {lab_pin.sym} 3120 -1605 0 0 {name=p13 sig_type=std_logic lab=df00_b}
C {lab_pin.sym} 1090 -1725 1 0 {name=p15 sig_type=std_logic lab=df6}
C {lab_pin.sym} 2540 -1725 1 0 {name=p19 sig_type=std_logic lab=df1}
C {lab_pin.sym} 2830 -1725 1 0 {name=p25 sig_type=std_logic lab=df0}
C {lab_pin.sym} 3120 -1725 1 0 {name=p27 sig_type=std_logic lab=df00}
C {lab_pin.sym} 1180 -1665 0 0 {name=p28 sig_type=std_logic lab=vdd
}
C {lab_pin.sym} 1380 -1605 0 0 {name=p29 sig_type=std_logic lab=df5_b}
C {lab_pin.sym} 1380 -1725 1 0 {name=p30 sig_type=std_logic lab=df5}
C {lab_pin.sym} 1470 -1665 0 0 {name=p31 sig_type=std_logic lab=vdd
}
C {lab_pin.sym} 1670 -1605 0 0 {name=p32 sig_type=std_logic lab=df4_b}
C {lab_pin.sym} 1670 -1725 1 0 {name=p33 sig_type=std_logic lab=df4}
C {lab_pin.sym} 1760 -1665 0 0 {name=p34 sig_type=std_logic lab=vdd
}
C {lab_pin.sym} 1960 -1605 0 0 {name=p37 sig_type=std_logic lab=df3_b}
C {lab_pin.sym} 1960 -1725 1 0 {name=p38 sig_type=std_logic lab=df3}
C {lab_pin.sym} 2050 -1665 0 0 {name=p42 sig_type=std_logic lab=vdd
}
C {lab_pin.sym} 2250 -1605 0 0 {name=p43 sig_type=std_logic lab=df2_b}
C {lab_pin.sym} 2250 -1725 1 0 {name=p44 sig_type=std_logic lab=df2}
C {lab_pin.sym} 2900 -1445 3 0 {name=p45 sig_type=std_logic lab=df00_b}
C {lab_pin.sym} 2610 -1445 3 0 {name=p46 sig_type=std_logic lab=df0_b}
C {lab_pin.sym} 1730 -1445 3 0 {name=p47 sig_type=std_logic lab=df3_b}
C {lab_pin.sym} 2020 -1445 3 0 {name=p48 sig_type=std_logic lab=df2_b}
C {lab_pin.sym} 2310 -1445 3 0 {name=p49 sig_type=std_logic lab=df1_b}
C {lab_pin.sym} 2240 -1275 2 0 {name=p50 sig_type=std_logic lab=b2}
C {lab_pin.sym} 1950 -1275 2 0 {name=p51 sig_type=std_logic lab=b3}
C {lab_pin.sym} 2530 -1275 2 0 {name=p52 sig_type=std_logic lab=b1}
C {lab_pin.sym} 2830 -1275 2 0 {name=p60 sig_type=std_logic lab=b0}
C {lab_pin.sym} 180 -1375 0 0 {name=p95 sig_type=std_logic lab=comp_in
}
C {lab_pin.sym} 1150 -1445 3 0 {name=p61 sig_type=std_logic lab=df5_b}
C {lab_pin.sym} 1440 -1445 3 0 {name=p63 sig_type=std_logic lab=df4_b}
C {lab_pin.sym} 1660 -1275 2 0 {name=p81 sig_type=std_logic lab=b4}
C {lab_pin.sym} 1370 -1275 2 0 {name=p82 sig_type=std_logic lab=b5}
C {lab_pin.sym} 1080 -1275 2 0 {name=p83 sig_type=std_logic lab=b6}
C {lab_pin.sym} 790 -1275 2 0 {name=p87 sig_type=std_logic lab=b7}
C {sky130_stdcells/dfbbp_1.sym} 980 -1695 0 0 {name=x35 VGND=vss VNB=vss VPB=vdd VPWR=vdd prefix=sky130_fd_sc_hd__ }
C {sky130_stdcells/dfbbp_1.sym} 1270 -1695 0 0 {name=x36 VGND=vss VNB=vss VPB=vdd VPWR=vdd prefix=sky130_fd_sc_hd__ }
C {sky130_stdcells/dfbbp_1.sym} 1560 -1695 0 0 {name=x37 VGND=vss VNB=vss VPB=vdd VPWR=vdd prefix=sky130_fd_sc_hd__ }
C {sky130_stdcells/dfbbp_1.sym} 1850 -1695 0 0 {name=x38 VGND=vss VNB=vss VPB=vdd VPWR=vdd prefix=sky130_fd_sc_hd__ }
C {sky130_stdcells/dfbbp_1.sym} 2140 -1695 0 0 {name=x39 VGND=vss VNB=vss VPB=vdd VPWR=vdd prefix=sky130_fd_sc_hd__ }
C {sky130_stdcells/dfbbp_1.sym} 2430 -1695 0 0 {name=x40 VGND=vss VNB=vss VPB=vdd VPWR=vdd prefix=sky130_fd_sc_hd__ }
C {sky130_stdcells/dfbbp_1.sym} 2720 -1695 0 0 {name=x41 VGND=vss VNB=vss VPB=vdd VPWR=vdd prefix=sky130_fd_sc_hd__ }
C {sky130_stdcells/dfbbp_1.sym} 3010 -1695 0 0 {name=x42 VGND=vss VNB=vss VPB=vdd VPWR=vdd prefix=sky130_fd_sc_hd__ }
C {sky130_stdcells/dfbbp_1.sym} 970 -1475 0 0 {name=x43 VGND=vss VNB=vss VPB=vdd VPWR=vdd prefix=sky130_fd_sc_hd__ }
C {sky130_stdcells/dfbbp_1.sym} 1260 -1475 0 0 {name=x44 VGND=vss VNB=vss VPB=vdd VPWR=vdd prefix=sky130_fd_sc_hd__ }
C {sky130_stdcells/dfbbp_1.sym} 1550 -1475 0 0 {name=x45 VGND=vss VNB=vss VPB=vdd VPWR=vdd prefix=sky130_fd_sc_hd__ }
C {sky130_stdcells/dfbbp_1.sym} 1840 -1475 0 0 {name=x46 VGND=vss VNB=vss VPB=vdd VPWR=vdd prefix=sky130_fd_sc_hd__ }
C {sky130_stdcells/dfbbp_1.sym} 2130 -1475 0 0 {name=x47 VGND=vss VNB=vss VPB=vdd VPWR=vdd prefix=sky130_fd_sc_hd__ }
C {sky130_stdcells/dfbbp_1.sym} 2420 -1475 0 0 {name=x48 VGND=vss VNB=vss VPB=vdd VPWR=vdd prefix=sky130_fd_sc_hd__ }
C {sky130_stdcells/dfbbp_1.sym} 2720 -1475 0 0 {name=x49 VGND=vss VNB=vss VPB=vdd VPWR=vdd prefix=sky130_fd_sc_hd__ }
C {sky130_stdcells/dfbbp_1.sym} 3010 -1475 0 0 {name=x50 VGND=vss VNB=vss VPB=vdd VPWR=vdd prefix=sky130_fd_sc_hd__ }
C {lab_pin.sym} 2920 -1505 0 0 {name=p88 sig_type=std_logic lab=vss
}
C {lab_pin.sym} 2920 -1485 0 0 {name=p89 sig_type=std_logic lab=vss
}
C {lab_pin.sym} 180 -1665 0 0 {name=p94 sig_type=std_logic lab=reset_n
}
C {lab_pin.sym} 800 -1605 0 0 {name=p98 sig_type=std_logic lab=df7_b}
C {lab_pin.sym} 800 -1725 1 0 {name=p99 sig_type=std_logic lab=df7}
C {sky130_stdcells/dfbbp_1.sym} 690 -1695 0 0 {name=x51 VGND=vss VNB=vss VPB=vdd VPWR=vdd prefix=sky130_fd_sc_hd__ }
C {sky130_stdcells/dfbbp_1.sym} 680 -1475 0 0 {name=x52 VGND=vss VNB=vss VPB=vdd VPWR=vdd prefix=sky130_fd_sc_hd__ }
C {lab_pin.sym} 860 -1445 3 0 {name=p102 sig_type=std_logic lab=df6_b}
C {sky130_stdcells/dfxbp_2.sym} 350 -1675 0 0 {name=x53 VGND=vss VNB=vss VPB=vdd VPWR=vdd prefix=sky130_fd_sc_hd__ }
C {lab_pin.sym} 570 -1685 0 0 {name=p103 sig_type=std_logic lab=vdd
}
C {sky130_stdcells/mux2_1.sym} 430 -1480 2 1 {name=x54 VGND=vss VNB=vss VPB=vdd VPWR=vdd prefix=sky130_fd_sc_hd__ }
C {lab_pin.sym} 390 -1460 0 0 {name=p104 sig_type=std_logic lab=vdd
}
C {lab_pin.sym} 390 -1500 0 0 {name=p107 sig_type=std_logic lab=df7_b}
C {sky130_stdcells/dfbbp_1.sym} 1135 -985 0 0 {name=x55 VGND=vss VNB=vss VPB=vdd VPWR=vdd prefix=sky130_fd_sc_hd__ }
C {sky130_stdcells/dfbbp_1.sym} 1125 -765 0 0 {name=x56 VGND=vss VNB=vss VPB=vdd VPWR=vdd prefix=sky130_fd_sc_hd__ }
C {devices/lab_pin.sym} 755 -995 0 0 {name=p108 lab=vss}
C {lab_pin.sym} 755 -975 0 0 {name=p109 sig_type=std_logic lab=vdd
}
C {lab_pin.sym} 955 -895 0 0 {name=p40 sig_type=std_logic lab=df8_b}
C {lab_pin.sym} 745 -735 0 0 {name=p110 sig_type=std_logic lab=df8_b}
C {lab_pin.sym} 335 -1055 0 0 {name=p12 sig_type=std_logic lab=clk}
C {lab_pin.sym} 340 -955 0 0 {name=p23 sig_type=std_logic lab=reset_n
}
C {sky130_stdcells/dfxbp_2.sym} 510 -965 0 0 {name=x57 VGND=vss VNB=vss VPB=vdd VPWR=vdd prefix=sky130_fd_sc_hd__ }
C {lab_pin.sym} 385 -665 0 0 {name=p111 sig_type=std_logic lab=comp_in
}
C {lab_pin.sym} 1040 -955 0 0 {name=p112 sig_type=std_logic lab=vdd
}
